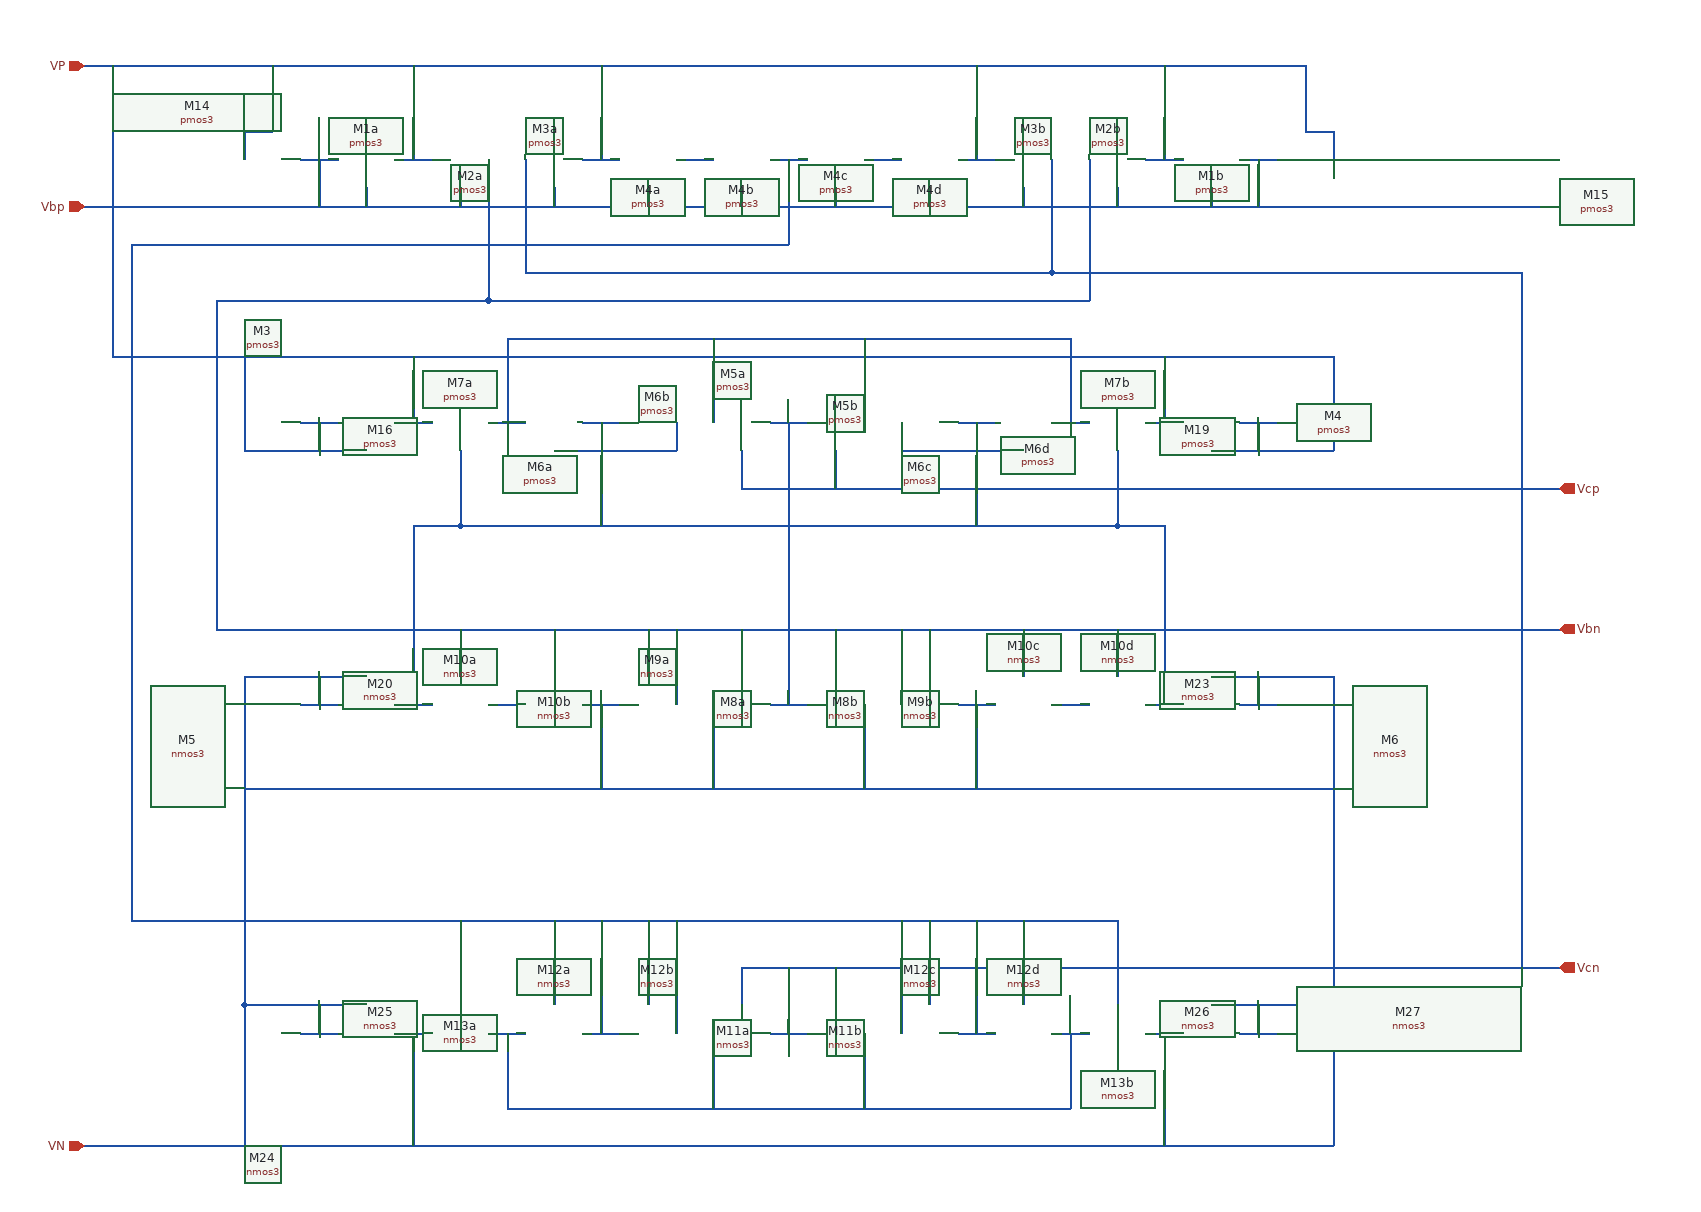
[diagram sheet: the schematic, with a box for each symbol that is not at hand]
v {xschem version=2.9.9 file_version=1.2 }
G {}
K {}
V {}
S {}
E {}
N 210 -1060 210 -1040 { lab=Vbp}
N 310 -1060 310 -1040 { lab=Vbp}
N 410 -1060 410 -1040 { lab=Vbp}
N 510 -1060 510 -1040 { lab=Vbp}
N 610 -1060 610 -1040 { lab=Vbp}
N 710 -1060 710 -1040 { lab=Vbp}
N 810 -1060 810 -1040 { lab=Vbp}
N 910 -1060 910 -1040 { lab=Vbp}
N 1010 -1060 1010 -1040 { lab=Vbp}
N 1110 -1060 1110 -1040 { lab=Vbp}
N 1140 -1090 1180 -1090 { lab=Vbp}
N 140 -1090 180 -1090 { lab=Vbp}
N 80 -1120 110 -1120 { lab=VP}
N 80 -1120 80 -1090 { lab=VP}
N 1210 -1190 1210 -1120 { lab=VP}
N 1210 -1120 1240 -1120 { lab=VP}
N 1240 -1120 1240 -1090 { lab=VP}
N 110 -1190 110 -1120 { lab=VP}
N 160 -1090 160 -1040 { lab=Vbp}
N 240 -1090 280 -1090 { lab=VP}
N 260 -1190 260 -1090 { lab=VP}
N 1040 -1090 1080 -1090 { lab=VP}
N 1060 -1190 1060 -1090 { lab=VP}
N 440 -1090 480 -1090 { lab=VP}
N 460 -1190 460 -1090 { lab=VP}
N 840 -1090 880 -1090 { lab=VP}
N 860 -1190 860 -1090 { lab=VP}
N 540 -1090 580 -1090 { lab=#net1}
N 740 -1090 780 -1090 { lab=#net2}
N 640 -1090 680 -1090 { lab=#net3}
N 140 -810 180 -810 { lab=VP}
N 110 -780 210 -780 { lab=VP}
N 80 -810 80 -780 { lab=VP}
N 80 -780 110 -780 { lab=VP}
N 160 -810 160 -780 { lab=VP}
N 240 -810 280 -810 { lab=VP}
N 340 -810 380 -810 { lab=#net4}
N 510 -780 540 -780 { lab=#net5}
N 540 -810 540 -780 { lab=#net5}
N 440 -810 480 -810 { lab=#net5}
N 410 -780 510 -780 { lab=#net5}
N 1110 -780 1210 -780 { lab=VP}
N 1210 -780 1240 -780 { lab=VP}
N 1240 -810 1240 -780 { lab=VP}
N 1140 -810 1180 -810 { lab=VP}
N 1160 -810 1160 -780 { lab=VP}
N 1040 -810 1080 -810 { lab=VP}
N 840 -810 880 -810 { lab=#net5}
N 940 -810 980 -810 { lab=#net4}
N 640 -810 680 -810 { lab=Vcp}
N 1240 -880 1240 -810 { lab=VP}
N 80 -880 80 -810 { lab=VP}
N 780 -810 780 -780 { lab=#net5}
N 780 -780 910 -780 { lab=#net5}
N 610 -740 1480 -740 { lab=Vcp}
N 610 -780 610 -740 { lab=Vcp}
N 710 -780 710 -740 { lab=Vcp}
N 660 -810 660 -740 { lab=Vcp}
N 310 -700 1010 -700 { lab=#net5}
N 1010 -780 1010 -700 { lab=#net5}
N 310 -780 310 -700 { lab=#net5}
N 460 -780 460 -700 { lab=#net5}
N 860 -780 860 -700 { lab=#net5}
N 360 -900 360 -810 { lab=#net4}
N 360 -900 960 -900 { lab=#net4}
N 960 -900 960 -810 { lab=#net4}
N 580 -900 580 -810 { lab=#net4}
N 740 -900 740 -810 { lab=#net4}
N 80 -540 80 -510 { lab=VN}
N 80 -540 210 -540 { lab=VN}
N 140 -510 180 -510 { lab=VN}
N 160 -540 160 -510 { lab=VN}
N 110 -190 210 -190 { lab=VN}
N 140 -160 180 -160 { lab=VN}
N 160 -190 160 -160 { lab=VN}
N 80 -190 80 -160 { lab=VN}
N 80 -190 110 -190 { lab=VN}
N 1140 -510 1180 -510 { lab=VN}
N 1240 -540 1240 -510 { lab=VN}
N 1110 -540 1240 -540 { lab=VN}
N 1160 -540 1160 -510 { lab=VN}
N 1140 -160 1180 -160 { lab=VN}
N 1240 -190 1240 -160 { lab=VN}
N 1110 -190 1240 -190 { lab=VN}
N 1160 -190 1160 -160 { lab=VN}
N 1240 -160 1240 -40 { lab=VN}
N 80 -160 80 -40 { lab=VN}
N 240 -160 280 -160 { lab=VN}
N 260 -160 260 -40 { lab=VN}
N 1040 -160 1080 -160 { lab=VN}
N 1060 -160 1060 -40 { lab=VN}
N 460 -810 460 -780 { lab=#net5}
N 860 -810 860 -780 { lab=#net5}
N 240 -510 280 -510 { lab=#net5}
N 340 -510 380 -510 { lab=#net6}
N 440 -510 480 -510 { lab=VN}
N 1040 -510 1080 -510 { lab=#net5}
N 940 -510 980 -510 { lab=#net6}
N 840 -510 880 -510 { lab=VN}
N 640 -510 680 -510 { lab=Vcp}
N 660 -740 660 -510 { lab=Vcp}
N 50 -590 1480 -590 { lab=Vbn}
N 610 -590 610 -540 { lab=Vbn}
N 710 -590 710 -540 { lab=Vbn}
N 1060 -700 1060 -510 { lab=#net5}
N 1010 -700 1060 -700 { lab=#net5}
N 260 -700 260 -510 { lab=#net5}
N 260 -700 310 -700 { lab=#net5}
N 510 -590 510 -540 { lab=Vbn}
N 540 -590 540 -510 { lab=Vbn}
N 780 -590 780 -510 { lab=Vbn}
N 810 -590 810 -540 { lab=Vbn}
N 310 -590 310 -540 { lab=Vbn}
N 410 -590 410 -540 { lab=Vbn}
N 910 -590 910 -540 { lab=Vbn}
N 1010 -590 1010 -540 { lab=Vbn}
N 460 -510 460 -420 { lab=VN}
N 80 -510 80 -190 { lab=VN}
N 1240 -510 1240 -190 { lab=VN}
N 860 -510 860 -420 { lab=VN}
N 80 -420 1240 -420 { lab=VN}
N 580 -510 580 -420 { lab=VN}
N 740 -510 740 -420 { lab=VN}
N 260 -880 260 -810 { lab=VP}
N 1060 -880 1060 -810 { lab=VP}
N 340 -160 380 -160 { lab=#net7}
N 440 -160 480 -160 { lab=#net3}
N 940 -160 980 -160 { lab=#net7}
N 840 -160 880 -160 { lab=#net3}
N 610 -230 1480 -230 { lab=Vcn}
N 610 -230 610 -190 { lab=Vcn}
N 710 -230 710 -190 { lab=Vcn}
N 640 -160 680 -160 { lab=Vcn}
N 660 -230 660 -160 { lab=Vcn}
N 1010 -280 1010 -190 { lab=#net3}
N 910 -280 910 -190 { lab=#net3}
N 810 -280 810 -190 { lab=#net3}
N 510 -280 510 -190 { lab=#net3}
N 410 -280 410 -190 { lab=#net3}
N 310 -280 310 -190 { lab=#net3}
N 540 -280 540 -160 { lab=#net3}
N 780 -280 780 -160 { lab=#net3}
N 460 -280 460 -160 { lab=#net3}
N 860 -280 860 -160 { lab=#net3}
N 360 -160 360 -80 { lab=#net7}
N 360 -80 960 -80 { lab=#net7}
N 960 -160 960 -80 { lab=#net7}
N 580 -160 580 -80 { lab=#net7}
N 740 -160 740 -80 { lab=#net7}
N 340 -940 980 -940 { lab=Vbn}
N 380 -970 940 -970 { lab=Vcn}
N 660 -1090 660 -1000 { lab=#net3}
N 980 -1090 980 -940 { lab=Vbn}
N 940 -1090 940 -970 { lab=Vcn}
N 380 -1090 380 -970 { lab=Vcn}
N 340 -1090 340 -940 { lab=Vbn}
N -90 -1190 1210 -1190 { lab=VP}
N -90 -1040 1460 -1040 { lab=Vbp}
N -60 -880 1240 -880 { lab=VP}
N -60 -1190 -60 -880 { lab=VP}
N -40 -280 1010 -280 { lab=#net3}
N -90 -40 1240 -40 { lab=VN}
N 940 -970 1440 -970 { lab=Vcn}
N 1440 -970 1440 -230 { lab=Vcn}
N 50 -940 50 -590 { lab=Vbn}
N 50 -940 340 -940 { lab=Vbn}
N -40 -1000 -40 -280 { lab=#net3}
N -40 -1000 660 -1000 { lab=#net3}
N 1160 -1090 1160 -1040 { lab=Vbp}
C {madvlsi/pmos3.sym} 210 -1090 3 0 {name=M1a
L=0.5
W=6
body=VDD
nf=1
mult=1
ad="'int((nf+1)/2) * W/nf * 0.29'" 
pd="'2*int((nf+1)/2) * (W/nf + 0.29)'"
as="'int((nf+2)/2) * W/nf * 0.29'" 
ps="'2*int((nf+2)/2) * (W/nf + 0.29)'"
nrd="'0.29 / W'" nrs="'0.29 / W'"
sa=0 sb=0 sd=0
model=pfet_01v8
spiceprefix=X
}
C {madvlsi/pmos3.sym} 310 -1090 3 0 {name=M2a
L=0.5
W=6
body=VDD
nf=1
mult=1
ad="'int((nf+1)/2) * W/nf * 0.29'" 
pd="'2*int((nf+1)/2) * (W/nf + 0.29)'"
as="'int((nf+2)/2) * W/nf * 0.29'" 
ps="'2*int((nf+2)/2) * (W/nf + 0.29)'"
nrd="'0.29 / W'" nrs="'0.29 / W'"
sa=0 sb=0 sd=0
model=pfet_01v8
spiceprefix=X
}
C {madvlsi/pmos3.sym} 410 -1090 3 0 {name=M3a
L=0.5
W=6
body=VDD
nf=1
mult=1
ad="'int((nf+1)/2) * W/nf * 0.29'" 
pd="'2*int((nf+1)/2) * (W/nf + 0.29)'"
as="'int((nf+2)/2) * W/nf * 0.29'" 
ps="'2*int((nf+2)/2) * (W/nf + 0.29)'"
nrd="'0.29 / W'" nrs="'0.29 / W'"
sa=0 sb=0 sd=0
model=pfet_01v8
spiceprefix=X
}
C {madvlsi/pmos3.sym} 510 -1090 3 0 {name=M4a
L=0.5
W=6
body=VDD
nf=1
mult=1
ad="'int((nf+1)/2) * W/nf * 0.29'" 
pd="'2*int((nf+1)/2) * (W/nf + 0.29)'"
as="'int((nf+2)/2) * W/nf * 0.29'" 
ps="'2*int((nf+2)/2) * (W/nf + 0.29)'"
nrd="'0.29 / W'" nrs="'0.29 / W'"
sa=0 sb=0 sd=0
model=pfet_01v8
spiceprefix=X
}
C {madvlsi/pmos3.sym} 710 -1090 3 0 {name=M4c
L=0.5
W=6
body=VDD
nf=1
mult=1
ad="'int((nf+1)/2) * W/nf * 0.29'" 
pd="'2*int((nf+1)/2) * (W/nf + 0.29)'"
as="'int((nf+2)/2) * W/nf * 0.29'" 
ps="'2*int((nf+2)/2) * (W/nf + 0.29)'"
nrd="'0.29 / W'" nrs="'0.29 / W'"
sa=0 sb=0 sd=0
model=pfet_01v8
spiceprefix=X
}
C {madvlsi/pmos3.sym} 910 -1090 3 0 {name=M3b
L=0.5
W=6
body=VDD
nf=1
mult=1
ad="'int((nf+1)/2) * W/nf * 0.29'" 
pd="'2*int((nf+1)/2) * (W/nf + 0.29)'"
as="'int((nf+2)/2) * W/nf * 0.29'" 
ps="'2*int((nf+2)/2) * (W/nf + 0.29)'"
nrd="'0.29 / W'" nrs="'0.29 / W'"
sa=0 sb=0 sd=0
model=pfet_01v8
spiceprefix=X
}
C {madvlsi/pmos3.sym} 1010 -1090 3 0 {name=M2b
L=0.5
W=6
body=VDD
nf=1
mult=1
ad="'int((nf+1)/2) * W/nf * 0.29'" 
pd="'2*int((nf+1)/2) * (W/nf + 0.29)'"
as="'int((nf+2)/2) * W/nf * 0.29'" 
ps="'2*int((nf+2)/2) * (W/nf + 0.29)'"
nrd="'0.29 / W'" nrs="'0.29 / W'"
sa=0 sb=0 sd=0
model=pfet_01v8
spiceprefix=X
}
C {madvlsi/pmos3.sym} 1110 -1090 3 0 {name=M1b
L=0.5
W=6
body=VDD
nf=1
mult=1
ad="'int((nf+1)/2) * W/nf * 0.29'" 
pd="'2*int((nf+1)/2) * (W/nf + 0.29)'"
as="'int((nf+2)/2) * W/nf * 0.29'" 
ps="'2*int((nf+2)/2) * (W/nf + 0.29)'"
nrd="'0.29 / W'" nrs="'0.29 / W'"
sa=0 sb=0 sd=0
model=pfet_01v8
spiceprefix=X
}
C {madvlsi/pmos3.sym} 410 -810 3 0 {name=M6a
L=0.5
W=6
body=VDD
nf=1
mult=1
ad="'int((nf+1)/2) * W/nf * 0.29'" 
pd="'2*int((nf+1)/2) * (W/nf + 0.29)'"
as="'int((nf+2)/2) * W/nf * 0.29'" 
ps="'2*int((nf+2)/2) * (W/nf + 0.29)'"
nrd="'0.29 / W'" nrs="'0.29 / W'"
sa=0 sb=0 sd=0
model=pfet_01v8
spiceprefix=X
}
C {madvlsi/pmos3.sym} 510 -810 3 0 {name=M6b
L=0.5
W=6
body=VDD
nf=1
mult=1
ad="'int((nf+1)/2) * W/nf * 0.29'" 
pd="'2*int((nf+1)/2) * (W/nf + 0.29)'"
as="'int((nf+2)/2) * W/nf * 0.29'" 
ps="'2*int((nf+2)/2) * (W/nf + 0.29)'"
nrd="'0.29 / W'" nrs="'0.29 / W'"
sa=0 sb=0 sd=0
model=pfet_01v8
spiceprefix=X
}
C {madvlsi/pmos3.sym} 610 -810 3 0 {name=M5a
L=0.5
W=6
body=VDD
nf=1
mult=1
ad="'int((nf+1)/2) * W/nf * 0.29'" 
pd="'2*int((nf+1)/2) * (W/nf + 0.29)'"
as="'int((nf+2)/2) * W/nf * 0.29'" 
ps="'2*int((nf+2)/2) * (W/nf + 0.29)'"
nrd="'0.29 / W'" nrs="'0.29 / W'"
sa=0 sb=0 sd=0
model=pfet_01v8
spiceprefix=X
}
C {madvlsi/pmos3.sym} 710 -810 3 0 {name=M5b
L=0.5
W=6
body=VDD
nf=1
mult=1
ad="'int((nf+1)/2) * W/nf * 0.29'" 
pd="'2*int((nf+1)/2) * (W/nf + 0.29)'"
as="'int((nf+2)/2) * W/nf * 0.29'" 
ps="'2*int((nf+2)/2) * (W/nf + 0.29)'"
nrd="'0.29 / W'" nrs="'0.29 / W'"
sa=0 sb=0 sd=0
model=pfet_01v8
spiceprefix=X
}
C {madvlsi/pmos3.sym} 810 -810 3 0 {name=M6c
L=0.5
W=6
body=VDD
nf=1
mult=1
ad="'int((nf+1)/2) * W/nf * 0.29'" 
pd="'2*int((nf+1)/2) * (W/nf + 0.29)'"
as="'int((nf+2)/2) * W/nf * 0.29'" 
ps="'2*int((nf+2)/2) * (W/nf + 0.29)'"
nrd="'0.29 / W'" nrs="'0.29 / W'"
sa=0 sb=0 sd=0
model=pfet_01v8
spiceprefix=X
}
C {madvlsi/pmos3.sym} 910 -810 3 0 {name=M6d
L=0.5
W=6
body=VDD
nf=1
mult=1
ad="'int((nf+1)/2) * W/nf * 0.29'" 
pd="'2*int((nf+1)/2) * (W/nf + 0.29)'"
as="'int((nf+2)/2) * W/nf * 0.29'" 
ps="'2*int((nf+2)/2) * (W/nf + 0.29)'"
nrd="'0.29 / W'" nrs="'0.29 / W'"
sa=0 sb=0 sd=0
model=pfet_01v8
spiceprefix=X
}
C {madvlsi/nmos3.sym} 610 -510 1 0 {name=M8a
L=0.5
W=6
body=GND
nf=1
mult=1
ad="'int((nf+1)/2) * W/nf * 0.29'" 
pd="'2*int((nf+1)/2) * (W/nf + 0.29)'"
as="'int((nf+2)/2) * W/nf * 0.29'" 
ps="'2*int((nf+2)/2) * (W/nf + 0.29)'"
nrd="'0.29 / W'" nrs="'0.29 / W'"
sa=0 sb=0 sd=0
model=nfet_01v8
spiceprefix=X
}
C {madvlsi/nmos3.sym} 710 -510 1 0 {name=M8b
L=0.5
W=6
body=GND
nf=1
mult=1
ad="'int((nf+1)/2) * W/nf * 0.29'" 
pd="'2*int((nf+1)/2) * (W/nf + 0.29)'"
as="'int((nf+2)/2) * W/nf * 0.29'" 
ps="'2*int((nf+2)/2) * (W/nf + 0.29)'"
nrd="'0.29 / W'" nrs="'0.29 / W'"
sa=0 sb=0 sd=0
model=nfet_01v8
spiceprefix=X
}
C {madvlsi/nmos3.sym} 410 -510 1 0 {name=M10b
L=0.5
W=6
body=GND
nf=1
mult=1
ad="'int((nf+1)/2) * W/nf * 0.29'" 
pd="'2*int((nf+1)/2) * (W/nf + 0.29)'"
as="'int((nf+2)/2) * W/nf * 0.29'" 
ps="'2*int((nf+2)/2) * (W/nf + 0.29)'"
nrd="'0.29 / W'" nrs="'0.29 / W'"
sa=0 sb=0 sd=0
model=nfet_01v8
spiceprefix=X
}
C {madvlsi/nmos3.sym} 510 -510 1 0 {name=M9a
L=0.5
W=6
body=GND
nf=1
mult=1
ad="'int((nf+1)/2) * W/nf * 0.29'" 
pd="'2*int((nf+1)/2) * (W/nf + 0.29)'"
as="'int((nf+2)/2) * W/nf * 0.29'" 
ps="'2*int((nf+2)/2) * (W/nf + 0.29)'"
nrd="'0.29 / W'" nrs="'0.29 / W'"
sa=0 sb=0 sd=0
model=nfet_01v8
spiceprefix=X
}
C {madvlsi/nmos3.sym} 810 -510 1 0 {name=M9b
L=0.5
W=6
body=GND
nf=1
mult=1
ad="'int((nf+1)/2) * W/nf * 0.29'" 
pd="'2*int((nf+1)/2) * (W/nf + 0.29)'"
as="'int((nf+2)/2) * W/nf * 0.29'" 
ps="'2*int((nf+2)/2) * (W/nf + 0.29)'"
nrd="'0.29 / W'" nrs="'0.29 / W'"
sa=0 sb=0 sd=0
model=nfet_01v8
spiceprefix=X
}
C {madvlsi/nmos3.sym} 910 -510 1 0 {name=M10c
L=0.5
W=6
body=GND
nf=1
mult=1
ad="'int((nf+1)/2) * W/nf * 0.29'" 
pd="'2*int((nf+1)/2) * (W/nf + 0.29)'"
as="'int((nf+2)/2) * W/nf * 0.29'" 
ps="'2*int((nf+2)/2) * (W/nf + 0.29)'"
nrd="'0.29 / W'" nrs="'0.29 / W'"
sa=0 sb=0 sd=0
model=nfet_01v8
spiceprefix=X
}
C {madvlsi/nmos3.sym} 610 -160 1 0 {name=M11a
L=0.5
W=6
body=GND
nf=1
mult=1
ad="'int((nf+1)/2) * W/nf * 0.29'" 
pd="'2*int((nf+1)/2) * (W/nf + 0.29)'"
as="'int((nf+2)/2) * W/nf * 0.29'" 
ps="'2*int((nf+2)/2) * (W/nf + 0.29)'"
nrd="'0.29 / W'" nrs="'0.29 / W'"
sa=0 sb=0 sd=0
model=nfet_01v8
spiceprefix=X
}
C {madvlsi/nmos3.sym} 710 -160 1 0 {name=M11b
L=0.5
W=6
body=GND
nf=1
mult=1
ad="'int((nf+1)/2) * W/nf * 0.29'" 
pd="'2*int((nf+1)/2) * (W/nf + 0.29)'"
as="'int((nf+2)/2) * W/nf * 0.29'" 
ps="'2*int((nf+2)/2) * (W/nf + 0.29)'"
nrd="'0.29 / W'" nrs="'0.29 / W'"
sa=0 sb=0 sd=0
model=nfet_01v8
spiceprefix=X
}
C {madvlsi/nmos3.sym} 310 -160 1 0 {name=M13a
L=0.5
W=6
body=GND
nf=1
mult=1
ad="'int((nf+1)/2) * W/nf * 0.29'" 
pd="'2*int((nf+1)/2) * (W/nf + 0.29)'"
as="'int((nf+2)/2) * W/nf * 0.29'" 
ps="'2*int((nf+2)/2) * (W/nf + 0.29)'"
nrd="'0.29 / W'" nrs="'0.29 / W'"
sa=0 sb=0 sd=0
model=nfet_01v8
spiceprefix=X
}
C {madvlsi/nmos3.sym} 410 -160 1 0 {name=M12a
L=0.5
W=6
body=GND
nf=1
mult=1
ad="'int((nf+1)/2) * W/nf * 0.29'" 
pd="'2*int((nf+1)/2) * (W/nf + 0.29)'"
as="'int((nf+2)/2) * W/nf * 0.29'" 
ps="'2*int((nf+2)/2) * (W/nf + 0.29)'"
nrd="'0.29 / W'" nrs="'0.29 / W'"
sa=0 sb=0 sd=0
model=nfet_01v8
spiceprefix=X
}
C {madvlsi/nmos3.sym} 910 -160 1 0 {name=M12d
L=0.5
W=6
body=GND
nf=1
mult=1
ad="'int((nf+1)/2) * W/nf * 0.29'" 
pd="'2*int((nf+1)/2) * (W/nf + 0.29)'"
as="'int((nf+2)/2) * W/nf * 0.29'" 
ps="'2*int((nf+2)/2) * (W/nf + 0.29)'"
nrd="'0.29 / W'" nrs="'0.29 / W'"
sa=0 sb=0 sd=0
model=nfet_01v8
spiceprefix=X
}
C {madvlsi/nmos3.sym} 1010 -160 1 0 {name=M13b
L=0.5
W=6
body=GND
nf=1
mult=1
ad="'int((nf+1)/2) * W/nf * 0.29'" 
pd="'2*int((nf+1)/2) * (W/nf + 0.29)'"
as="'int((nf+2)/2) * W/nf * 0.29'" 
ps="'2*int((nf+2)/2) * (W/nf + 0.29)'"
nrd="'0.29 / W'" nrs="'0.29 / W'"
sa=0 sb=0 sd=0
model=nfet_01v8
spiceprefix=X
}
C {devices/iopin.sym} -90 -1190 2 0 {name=p1 lab=VP}
C {devices/iopin.sym} -90 -40 2 0 {name=p3 lab=VN}
C {devices/opin.sym} 1480 -740 0 0 {name=p5 lab=Vcp}
C {devices/opin.sym} 1480 -590 0 0 {name=p6 lab=Vbn}
C {devices/opin.sym} 1480 -230 0 0 {name=p7 lab=Vcn
}
C {madvlsi/pmos3.sym} 1210 -1090 1 0 {name=M15
L=0.5
W=6
body=VDD
nf=1
mult=1
ad="'int((nf+1)/2) * W/nf * 0.29'" 
pd="'2*int((nf+1)/2) * (W/nf + 0.29)'"
as="'int((nf+2)/2) * W/nf * 0.29'" 
ps="'2*int((nf+2)/2) * (W/nf + 0.29)'"
nrd="'0.29 / W'" nrs="'0.29 / W'"
sa=0 sb=0 sd=0
model=pfet_01v8
spiceprefix=X
}
C {madvlsi/nmos3.sym} 210 -160 1 0 {name=M25
L=0.5
W=6
body=GND
nf=1
mult=1
ad="'int((nf+1)/2) * W/nf * 0.29'" 
pd="'2*int((nf+1)/2) * (W/nf + 0.29)'"
as="'int((nf+2)/2) * W/nf * 0.29'" 
ps="'2*int((nf+2)/2) * (W/nf + 0.29)'"
nrd="'0.29 / W'" nrs="'0.29 / W'"
sa=0 sb=0 sd=0
model=nfet_01v8
spiceprefix=X
}
C {madvlsi/nmos3.sym} 110 -160 1 0 {name=M24
L=0.5
W=6
body=GND
nf=1
mult=1
ad="'int((nf+1)/2) * W/nf * 0.29'" 
pd="'2*int((nf+1)/2) * (W/nf + 0.29)'"
as="'int((nf+2)/2) * W/nf * 0.29'" 
ps="'2*int((nf+2)/2) * (W/nf + 0.29)'"
nrd="'0.29 / W'" nrs="'0.29 / W'"
sa=0 sb=0 sd=0
model=nfet_01v8
spiceprefix=X
}
C {madvlsi/nmos3.sym} 1110 -160 1 0 {name=M26
L=0.5
W=6
body=GND
nf=1
mult=1
ad="'int((nf+1)/2) * W/nf * 0.29'" 
pd="'2*int((nf+1)/2) * (W/nf + 0.29)'"
as="'int((nf+2)/2) * W/nf * 0.29'" 
ps="'2*int((nf+2)/2) * (W/nf + 0.29)'"
nrd="'0.29 / W'" nrs="'0.29 / W'"
sa=0 sb=0 sd=0
model=nfet_01v8
spiceprefix=X
}
C {madvlsi/nmos3.sym} 1210 -160 1 0 {name=M27
L=0.5
W=6
body=GND
nf=1
mult=1
ad="'int((nf+1)/2) * W/nf * 0.29'" 
pd="'2*int((nf+1)/2) * (W/nf + 0.29)'"
as="'int((nf+2)/2) * W/nf * 0.29'" 
ps="'2*int((nf+2)/2) * (W/nf + 0.29)'"
nrd="'0.29 / W'" nrs="'0.29 / W'"
sa=0 sb=0 sd=0
model=nfet_01v8
spiceprefix=X
}
C {madvlsi/nmos3.sym} 310 -510 1 0 {name=M10a
L=0.5
W=6
body=GND
nf=1
mult=1
ad="'int((nf+1)/2) * W/nf * 0.29'" 
pd="'2*int((nf+1)/2) * (W/nf + 0.29)'"
as="'int((nf+2)/2) * W/nf * 0.29'" 
ps="'2*int((nf+2)/2) * (W/nf + 0.29)'"
nrd="'0.29 / W'" nrs="'0.29 / W'"
sa=0 sb=0 sd=0
model=nfet_01v8
spiceprefix=X
}
C {madvlsi/nmos3.sym} 210 -510 1 0 {name=M20
L=0.5
W=6
body=GND
nf=1
mult=1
ad="'int((nf+1)/2) * W/nf * 0.29'" 
pd="'2*int((nf+1)/2) * (W/nf + 0.29)'"
as="'int((nf+2)/2) * W/nf * 0.29'" 
ps="'2*int((nf+2)/2) * (W/nf + 0.29)'"
nrd="'0.29 / W'" nrs="'0.29 / W'"
sa=0 sb=0 sd=0
model=nfet_01v8
spiceprefix=X
}
C {madvlsi/nmos3.sym} 1110 -510 1 0 {name=M23
L=0.5
W=6
body=GND
nf=1
mult=1
ad="'int((nf+1)/2) * W/nf * 0.29'" 
pd="'2*int((nf+1)/2) * (W/nf + 0.29)'"
as="'int((nf+2)/2) * W/nf * 0.29'" 
ps="'2*int((nf+2)/2) * (W/nf + 0.29)'"
nrd="'0.29 / W'" nrs="'0.29 / W'"
sa=0 sb=0 sd=0
model=nfet_01v8
spiceprefix=X
}
C {madvlsi/nmos3.sym} 1010 -510 1 0 {name=M10d
L=0.5
W=6
body=GND
nf=1
mult=1
ad="'int((nf+1)/2) * W/nf * 0.29'" 
pd="'2*int((nf+1)/2) * (W/nf + 0.29)'"
as="'int((nf+2)/2) * W/nf * 0.29'" 
ps="'2*int((nf+2)/2) * (W/nf + 0.29)'"
nrd="'0.29 / W'" nrs="'0.29 / W'"
sa=0 sb=0 sd=0
model=nfet_01v8
spiceprefix=X
}
C {madvlsi/pmos3.sym} 110 -1090 1 0 {name=M14
L=0.5
W=6
body=VDD
nf=1
mult=1
ad="'int((nf+1)/2) * W/nf * 0.29'" 
pd="'2*int((nf+1)/2) * (W/nf + 0.29)'"
as="'int((nf+2)/2) * W/nf * 0.29'" 
ps="'2*int((nf+2)/2) * (W/nf + 0.29)'"
nrd="'0.29 / W'" nrs="'0.29 / W'"
sa=0 sb=0 sd=0
model=pfet_01v8
spiceprefix=X
}
C {madvlsi/pmos3.sym} 310 -810 3 0 {name=M7a
L=0.5
W=6
body=VDD
nf=1
mult=1
ad="'int((nf+1)/2) * W/nf * 0.29'" 
pd="'2*int((nf+1)/2) * (W/nf + 0.29)'"
as="'int((nf+2)/2) * W/nf * 0.29'" 
ps="'2*int((nf+2)/2) * (W/nf + 0.29)'"
nrd="'0.29 / W'" nrs="'0.29 / W'"
sa=0 sb=0 sd=0
model=pfet_01v8
spiceprefix=X
}
C {madvlsi/pmos3.sym} 210 -810 3 0 {name=M16
L=0.5
W=6
body=VDD
nf=1
mult=1
ad="'int((nf+1)/2) * W/nf * 0.29'" 
pd="'2*int((nf+1)/2) * (W/nf + 0.29)'"
as="'int((nf+2)/2) * W/nf * 0.29'" 
ps="'2*int((nf+2)/2) * (W/nf + 0.29)'"
nrd="'0.29 / W'" nrs="'0.29 / W'"
sa=0 sb=0 sd=0
model=pfet_01v8
spiceprefix=X
}
C {madvlsi/pmos3.sym} 1010 -810 3 0 {name=M7b
L=0.5
W=6
body=VDD
nf=1
mult=1
ad="'int((nf+1)/2) * W/nf * 0.29'" 
pd="'2*int((nf+1)/2) * (W/nf + 0.29)'"
as="'int((nf+2)/2) * W/nf * 0.29'" 
ps="'2*int((nf+2)/2) * (W/nf + 0.29)'"
nrd="'0.29 / W'" nrs="'0.29 / W'"
sa=0 sb=0 sd=0
model=pfet_01v8
spiceprefix=X
}
C {madvlsi/pmos3.sym} 1110 -810 3 0 {name=M19
L=0.5
W=6
body=VDD
nf=1
mult=1
ad="'int((nf+1)/2) * W/nf * 0.29'" 
pd="'2*int((nf+1)/2) * (W/nf + 0.29)'"
as="'int((nf+2)/2) * W/nf * 0.29'" 
ps="'2*int((nf+2)/2) * (W/nf + 0.29)'"
nrd="'0.29 / W'" nrs="'0.29 / W'"
sa=0 sb=0 sd=0
model=pfet_01v8
spiceprefix=X
}
C {devices/iopin.sym} -90 -1040 2 0 {name=p4 lab=Vbp}
C {madvlsi/pmos3.sym} 610 -1090 3 0 {name=M4b
L=0.5
W=6
body=VDD
nf=1
mult=1
ad="'int((nf+1)/2) * W/nf * 0.29'" 
pd="'2*int((nf+1)/2) * (W/nf + 0.29)'"
as="'int((nf+2)/2) * W/nf * 0.29'" 
ps="'2*int((nf+2)/2) * (W/nf + 0.29)'"
nrd="'0.29 / W'" nrs="'0.29 / W'"
sa=0 sb=0 sd=0
model=pfet_01v8
spiceprefix=X
}
C {madvlsi/pmos3.sym} 810 -1090 3 0 {name=M4d
L=0.5
W=6
body=VDD
nf=1
mult=1
ad="'int((nf+1)/2) * W/nf * 0.29'" 
pd="'2*int((nf+1)/2) * (W/nf + 0.29)'"
as="'int((nf+2)/2) * W/nf * 0.29'" 
ps="'2*int((nf+2)/2) * (W/nf + 0.29)'"
nrd="'0.29 / W'" nrs="'0.29 / W'"
sa=0 sb=0 sd=0
model=pfet_01v8
spiceprefix=X
}
C {madvlsi/pmos3.sym} 110 -810 3 0 {name=M3
L=0.5
W=6
body=VDD
nf=1
mult=1
ad="'int((nf+1)/2) * W/nf * 0.29'" 
pd="'2*int((nf+1)/2) * (W/nf + 0.29)'"
as="'int((nf+2)/2) * W/nf * 0.29'" 
ps="'2*int((nf+2)/2) * (W/nf + 0.29)'"
nrd="'0.29 / W'" nrs="'0.29 / W'"
sa=0 sb=0 sd=0
model=pfet_01v8
spiceprefix=X
}
C {madvlsi/pmos3.sym} 1210 -810 3 0 {name=M4
L=0.5
W=6
body=VDD
nf=1
mult=1
ad="'int((nf+1)/2) * W/nf * 0.29'" 
pd="'2*int((nf+1)/2) * (W/nf + 0.29)'"
as="'int((nf+2)/2) * W/nf * 0.29'" 
ps="'2*int((nf+2)/2) * (W/nf + 0.29)'"
nrd="'0.29 / W'" nrs="'0.29 / W'"
sa=0 sb=0 sd=0
model=pfet_01v8
spiceprefix=X
}
C {madvlsi/nmos3.sym} 110 -510 1 0 {name=M5
L=0.5
W=6
body=GND
nf=1
mult=1
ad="'int((nf+1)/2) * W/nf * 0.29'" 
pd="'2*int((nf+1)/2) * (W/nf + 0.29)'"
as="'int((nf+2)/2) * W/nf * 0.29'" 
ps="'2*int((nf+2)/2) * (W/nf + 0.29)'"
nrd="'0.29 / W'" nrs="'0.29 / W'"
sa=0 sb=0 sd=0
model=nfet_01v8
spiceprefix=X
}
C {madvlsi/nmos3.sym} 1210 -510 1 0 {name=M6
L=0.5
W=6
body=GND
nf=1
mult=1
ad="'int((nf+1)/2) * W/nf * 0.29'" 
pd="'2*int((nf+1)/2) * (W/nf + 0.29)'"
as="'int((nf+2)/2) * W/nf * 0.29'" 
ps="'2*int((nf+2)/2) * (W/nf + 0.29)'"
nrd="'0.29 / W'" nrs="'0.29 / W'"
sa=0 sb=0 sd=0
model=nfet_01v8
spiceprefix=X
}
C {madvlsi/nmos3.sym} 810 -160 1 0 {name=M12c
L=0.5
W=6
body=GND
nf=1
mult=1
ad="'int((nf+1)/2) * W/nf * 0.29'" 
pd="'2*int((nf+1)/2) * (W/nf + 0.29)'"
as="'int((nf+2)/2) * W/nf * 0.29'" 
ps="'2*int((nf+2)/2) * (W/nf + 0.29)'"
nrd="'0.29 / W'" nrs="'0.29 / W'"
sa=0 sb=0 sd=0
model=nfet_01v8
spiceprefix=X
}
C {madvlsi/nmos3.sym} 510 -160 1 0 {name=M12b
L=0.5
W=6
body=GND
nf=1
mult=1
ad="'int((nf+1)/2) * W/nf * 0.29'" 
pd="'2*int((nf+1)/2) * (W/nf + 0.29)'"
as="'int((nf+2)/2) * W/nf * 0.29'" 
ps="'2*int((nf+2)/2) * (W/nf + 0.29)'"
nrd="'0.29 / W'" nrs="'0.29 / W'"
sa=0 sb=0 sd=0
model=nfet_01v8
spiceprefix=X
}
